VERSION 5.7 ;
BUSBITCHARS "[]" ;
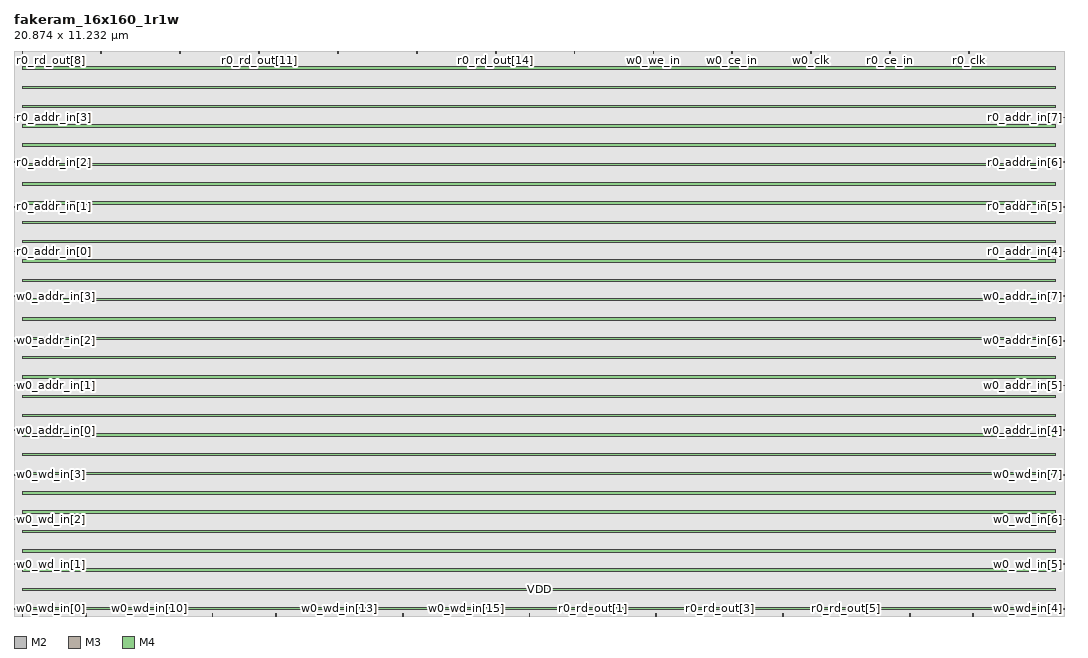
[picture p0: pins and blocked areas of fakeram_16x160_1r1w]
MACRO fakeram_16x160_1r1w
  FOREIGN fakeram_16x160_1r1w 0 0 ;
  SYMMETRY X Y R90 ;
  SIZE 20.874 BY 11.232 ;
  CLASS BLOCK ;
  PIN w0_wd_in[0]
    DIRECTION INPUT ;
    USE SIGNAL ;
    SHAPE ABUTMENT ;
    PORT
      LAYER M2 ;
      RECT 0.000 0.138 0.036 0.150 ;
    END
  END w0_wd_in[0]
  PIN w0_wd_in[1]
    DIRECTION INPUT ;
    USE SIGNAL ;
    SHAPE ABUTMENT ;
    PORT
      LAYER M2 ;
      RECT 0.000 1.026 0.036 1.038 ;
    END
  END w0_wd_in[1]
  PIN w0_wd_in[2]
    DIRECTION INPUT ;
    USE SIGNAL ;
    SHAPE ABUTMENT ;
    PORT
      LAYER M2 ;
      RECT 0.000 1.914 0.036 1.926 ;
    END
  END w0_wd_in[2]
  PIN w0_wd_in[3]
    DIRECTION INPUT ;
    USE SIGNAL ;
    SHAPE ABUTMENT ;
    PORT
      LAYER M2 ;
      RECT 0.000 2.802 0.036 2.814 ;
    END
  END w0_wd_in[3]
  PIN w0_wd_in[4]
    DIRECTION INPUT ;
    USE SIGNAL ;
    SHAPE ABUTMENT ;
    PORT
      LAYER M2 ;
      RECT 20.838 0.138 20.874 0.150 ;
    END
  END w0_wd_in[4]
  PIN w0_wd_in[5]
    DIRECTION INPUT ;
    USE SIGNAL ;
    SHAPE ABUTMENT ;
    PORT
      LAYER M2 ;
      RECT 20.838 1.026 20.874 1.038 ;
    END
  END w0_wd_in[5]
  PIN w0_wd_in[6]
    DIRECTION INPUT ;
    USE SIGNAL ;
    SHAPE ABUTMENT ;
    PORT
      LAYER M2 ;
      RECT 20.838 1.914 20.874 1.926 ;
    END
  END w0_wd_in[6]
  PIN w0_wd_in[7]
    DIRECTION INPUT ;
    USE SIGNAL ;
    SHAPE ABUTMENT ;
    PORT
      LAYER M2 ;
      RECT 20.838 2.802 20.874 2.814 ;
    END
  END w0_wd_in[7]
  PIN w0_wd_in[8]
    DIRECTION INPUT ;
    USE SIGNAL ;
    SHAPE ABUTMENT ;
    PORT
      LAYER M3 ;
      RECT 0.161 0.000 0.175 0.042 ;
    END
  END w0_wd_in[8]
  PIN w0_wd_in[9]
    DIRECTION INPUT ;
    USE SIGNAL ;
    SHAPE ABUTMENT ;
    PORT
      LAYER M3 ;
      RECT 1.421 0.000 1.435 0.042 ;
    END
  END w0_wd_in[9]
  PIN w0_wd_in[10]
    DIRECTION INPUT ;
    USE SIGNAL ;
    SHAPE ABUTMENT ;
    PORT
      LAYER M3 ;
      RECT 2.681 0.000 2.695 0.042 ;
    END
  END w0_wd_in[10]
  PIN w0_wd_in[11]
    DIRECTION INPUT ;
    USE SIGNAL ;
    SHAPE ABUTMENT ;
    PORT
      LAYER M3 ;
      RECT 3.941 0.000 3.955 0.042 ;
    END
  END w0_wd_in[11]
  PIN w0_wd_in[12]
    DIRECTION INPUT ;
    USE SIGNAL ;
    SHAPE ABUTMENT ;
    PORT
      LAYER M3 ;
      RECT 5.201 0.000 5.215 0.042 ;
    END
  END w0_wd_in[12]
  PIN w0_wd_in[13]
    DIRECTION INPUT ;
    USE SIGNAL ;
    SHAPE ABUTMENT ;
    PORT
      LAYER M3 ;
      RECT 6.461 0.000 6.475 0.042 ;
    END
  END w0_wd_in[13]
  PIN w0_wd_in[14]
    DIRECTION INPUT ;
    USE SIGNAL ;
    SHAPE ABUTMENT ;
    PORT
      LAYER M3 ;
      RECT 7.721 0.000 7.735 0.042 ;
    END
  END w0_wd_in[14]
  PIN w0_wd_in[15]
    DIRECTION INPUT ;
    USE SIGNAL ;
    SHAPE ABUTMENT ;
    PORT
      LAYER M3 ;
      RECT 8.981 0.000 8.995 0.042 ;
    END
  END w0_wd_in[15]
  PIN r0_rd_out[0]
    DIRECTION OUTPUT ;
    USE SIGNAL ;
    SHAPE ABUTMENT ;
    PORT
      LAYER M3 ;
      RECT 10.241 0.000 10.255 0.042 ;
    END
  END r0_rd_out[0]
  PIN r0_rd_out[1]
    DIRECTION OUTPUT ;
    USE SIGNAL ;
    SHAPE ABUTMENT ;
    PORT
      LAYER M3 ;
      RECT 11.501 0.000 11.515 0.042 ;
    END
  END r0_rd_out[1]
  PIN r0_rd_out[2]
    DIRECTION OUTPUT ;
    USE SIGNAL ;
    SHAPE ABUTMENT ;
    PORT
      LAYER M3 ;
      RECT 12.761 0.000 12.775 0.042 ;
    END
  END r0_rd_out[2]
  PIN r0_rd_out[3]
    DIRECTION OUTPUT ;
    USE SIGNAL ;
    SHAPE ABUTMENT ;
    PORT
      LAYER M3 ;
      RECT 14.021 0.000 14.035 0.042 ;
    END
  END r0_rd_out[3]
  PIN r0_rd_out[4]
    DIRECTION OUTPUT ;
    USE SIGNAL ;
    SHAPE ABUTMENT ;
    PORT
      LAYER M3 ;
      RECT 15.281 0.000 15.295 0.042 ;
    END
  END r0_rd_out[4]
  PIN r0_rd_out[5]
    DIRECTION OUTPUT ;
    USE SIGNAL ;
    SHAPE ABUTMENT ;
    PORT
      LAYER M3 ;
      RECT 16.541 0.000 16.555 0.042 ;
    END
  END r0_rd_out[5]
  PIN r0_rd_out[6]
    DIRECTION OUTPUT ;
    USE SIGNAL ;
    SHAPE ABUTMENT ;
    PORT
      LAYER M3 ;
      RECT 17.801 0.000 17.815 0.042 ;
    END
  END r0_rd_out[6]
  PIN r0_rd_out[7]
    DIRECTION OUTPUT ;
    USE SIGNAL ;
    SHAPE ABUTMENT ;
    PORT
      LAYER M3 ;
      RECT 19.061 0.000 19.075 0.042 ;
    END
  END r0_rd_out[7]
  PIN r0_rd_out[8]
    DIRECTION OUTPUT ;
    USE SIGNAL ;
    SHAPE ABUTMENT ;
    PORT
      LAYER M3 ;
      RECT 0.161 11.190 0.175 11.232 ;
    END
  END r0_rd_out[8]
  PIN r0_rd_out[9]
    DIRECTION OUTPUT ;
    USE SIGNAL ;
    SHAPE ABUTMENT ;
    PORT
      LAYER M3 ;
      RECT 1.729 11.190 1.743 11.232 ;
    END
  END r0_rd_out[9]
  PIN r0_rd_out[10]
    DIRECTION OUTPUT ;
    USE SIGNAL ;
    SHAPE ABUTMENT ;
    PORT
      LAYER M3 ;
      RECT 3.297 11.190 3.311 11.232 ;
    END
  END r0_rd_out[10]
  PIN r0_rd_out[11]
    DIRECTION OUTPUT ;
    USE SIGNAL ;
    SHAPE ABUTMENT ;
    PORT
      LAYER M3 ;
      RECT 4.865 11.190 4.879 11.232 ;
    END
  END r0_rd_out[11]
  PIN r0_rd_out[12]
    DIRECTION OUTPUT ;
    USE SIGNAL ;
    SHAPE ABUTMENT ;
    PORT
      LAYER M3 ;
      RECT 6.433 11.190 6.447 11.232 ;
    END
  END r0_rd_out[12]
  PIN r0_rd_out[13]
    DIRECTION OUTPUT ;
    USE SIGNAL ;
    SHAPE ABUTMENT ;
    PORT
      LAYER M3 ;
      RECT 8.001 11.190 8.015 11.232 ;
    END
  END r0_rd_out[13]
  PIN r0_rd_out[14]
    DIRECTION OUTPUT ;
    USE SIGNAL ;
    SHAPE ABUTMENT ;
    PORT
      LAYER M3 ;
      RECT 9.569 11.190 9.583 11.232 ;
    END
  END r0_rd_out[14]
  PIN r0_rd_out[15]
    DIRECTION OUTPUT ;
    USE SIGNAL ;
    SHAPE ABUTMENT ;
    PORT
      LAYER M3 ;
      RECT 11.137 11.190 11.151 11.232 ;
    END
  END r0_rd_out[15]
  PIN w0_addr_in[0]
    DIRECTION INPUT ;
    USE SIGNAL ;
    SHAPE ABUTMENT ;
    PORT
      LAYER M2 ;
      RECT 0.000 3.690 0.036 3.702 ;
    END
  END w0_addr_in[0]
  PIN w0_addr_in[1]
    DIRECTION INPUT ;
    USE SIGNAL ;
    SHAPE ABUTMENT ;
    PORT
      LAYER M2 ;
      RECT 0.000 4.578 0.036 4.590 ;
    END
  END w0_addr_in[1]
  PIN w0_addr_in[2]
    DIRECTION INPUT ;
    USE SIGNAL ;
    SHAPE ABUTMENT ;
    PORT
      LAYER M2 ;
      RECT 0.000 5.466 0.036 5.478 ;
    END
  END w0_addr_in[2]
  PIN w0_addr_in[3]
    DIRECTION INPUT ;
    USE SIGNAL ;
    SHAPE ABUTMENT ;
    PORT
      LAYER M2 ;
      RECT 0.000 6.354 0.036 6.366 ;
    END
  END w0_addr_in[3]
  PIN w0_addr_in[4]
    DIRECTION INPUT ;
    USE SIGNAL ;
    SHAPE ABUTMENT ;
    PORT
      LAYER M2 ;
      RECT 20.838 3.690 20.874 3.702 ;
    END
  END w0_addr_in[4]
  PIN w0_addr_in[5]
    DIRECTION INPUT ;
    USE SIGNAL ;
    SHAPE ABUTMENT ;
    PORT
      LAYER M2 ;
      RECT 20.838 4.578 20.874 4.590 ;
    END
  END w0_addr_in[5]
  PIN w0_addr_in[6]
    DIRECTION INPUT ;
    USE SIGNAL ;
    SHAPE ABUTMENT ;
    PORT
      LAYER M2 ;
      RECT 20.838 5.466 20.874 5.478 ;
    END
  END w0_addr_in[6]
  PIN w0_addr_in[7]
    DIRECTION INPUT ;
    USE SIGNAL ;
    SHAPE ABUTMENT ;
    PORT
      LAYER M2 ;
      RECT 20.838 6.354 20.874 6.366 ;
    END
  END w0_addr_in[7]
  PIN r0_addr_in[0]
    DIRECTION INPUT ;
    USE SIGNAL ;
    SHAPE ABUTMENT ;
    PORT
      LAYER M2 ;
      RECT 0.000 7.242 0.036 7.254 ;
    END
  END r0_addr_in[0]
  PIN r0_addr_in[1]
    DIRECTION INPUT ;
    USE SIGNAL ;
    SHAPE ABUTMENT ;
    PORT
      LAYER M2 ;
      RECT 0.000 8.130 0.036 8.142 ;
    END
  END r0_addr_in[1]
  PIN r0_addr_in[2]
    DIRECTION INPUT ;
    USE SIGNAL ;
    SHAPE ABUTMENT ;
    PORT
      LAYER M2 ;
      RECT 0.000 9.018 0.036 9.030 ;
    END
  END r0_addr_in[2]
  PIN r0_addr_in[3]
    DIRECTION INPUT ;
    USE SIGNAL ;
    SHAPE ABUTMENT ;
    PORT
      LAYER M2 ;
      RECT 0.000 9.906 0.036 9.918 ;
    END
  END r0_addr_in[3]
  PIN r0_addr_in[4]
    DIRECTION INPUT ;
    USE SIGNAL ;
    SHAPE ABUTMENT ;
    PORT
      LAYER M2 ;
      RECT 20.838 7.242 20.874 7.254 ;
    END
  END r0_addr_in[4]
  PIN r0_addr_in[5]
    DIRECTION INPUT ;
    USE SIGNAL ;
    SHAPE ABUTMENT ;
    PORT
      LAYER M2 ;
      RECT 20.838 8.130 20.874 8.142 ;
    END
  END r0_addr_in[5]
  PIN r0_addr_in[6]
    DIRECTION INPUT ;
    USE SIGNAL ;
    SHAPE ABUTMENT ;
    PORT
      LAYER M2 ;
      RECT 20.838 9.018 20.874 9.030 ;
    END
  END r0_addr_in[6]
  PIN r0_addr_in[7]
    DIRECTION INPUT ;
    USE SIGNAL ;
    SHAPE ABUTMENT ;
    PORT
      LAYER M2 ;
      RECT 20.838 9.906 20.874 9.918 ;
    END
  END r0_addr_in[7]
  PIN w0_we_in
    DIRECTION INPUT ;
    USE SIGNAL ;
    SHAPE ABUTMENT ;
    PORT
      LAYER M3 ;
      RECT 12.705 11.190 12.719 11.232 ;
    END
  END w0_we_in
  PIN w0_ce_in
    DIRECTION INPUT ;
    USE SIGNAL ;
    SHAPE ABUTMENT ;
    PORT
      LAYER M3 ;
      RECT 14.273 11.190 14.287 11.232 ;
    END
  END w0_ce_in
  PIN w0_clk
    DIRECTION INPUT ;
    USE SIGNAL ;
    SHAPE ABUTMENT ;
    PORT
      LAYER M3 ;
      RECT 15.841 11.190 15.855 11.232 ;
    END
  END w0_clk
  PIN r0_ce_in
    DIRECTION INPUT ;
    USE SIGNAL ;
    SHAPE ABUTMENT ;
    PORT
      LAYER M3 ;
      RECT 17.409 11.190 17.423 11.232 ;
    END
  END r0_ce_in
  PIN r0_clk
    DIRECTION INPUT ;
    USE SIGNAL ;
    SHAPE ABUTMENT ;
    PORT
      LAYER M3 ;
      RECT 18.977 11.190 18.991 11.232 ;
    END
  END r0_clk
  PIN VSS
    DIRECTION INOUT ;
    USE GROUND ;
    PORT
      LAYER M4 ;
      RECT 0.168 0.120 20.706 0.168 ;
      RECT 0.168 0.504 20.706 0.552 ;
      RECT 0.168 0.888 20.706 0.936 ;
      RECT 0.168 1.272 20.706 1.320 ;
      RECT 0.168 1.656 20.706 1.704 ;
      RECT 0.168 2.040 20.706 2.088 ;
      RECT 0.168 2.424 20.706 2.472 ;
      RECT 0.168 2.808 20.706 2.856 ;
      RECT 0.168 3.192 20.706 3.240 ;
      RECT 0.168 3.576 20.706 3.624 ;
      RECT 0.168 3.960 20.706 4.008 ;
      RECT 0.168 4.344 20.706 4.392 ;
      RECT 0.168 4.728 20.706 4.776 ;
      RECT 0.168 5.112 20.706 5.160 ;
      RECT 0.168 5.496 20.706 5.544 ;
      RECT 0.168 5.880 20.706 5.928 ;
      RECT 0.168 6.264 20.706 6.312 ;
      RECT 0.168 6.648 20.706 6.696 ;
      RECT 0.168 7.032 20.706 7.080 ;
      RECT 0.168 7.416 20.706 7.464 ;
      RECT 0.168 7.800 20.706 7.848 ;
      RECT 0.168 8.184 20.706 8.232 ;
      RECT 0.168 8.568 20.706 8.616 ;
      RECT 0.168 8.952 20.706 9.000 ;
      RECT 0.168 9.336 20.706 9.384 ;
      RECT 0.168 9.720 20.706 9.768 ;
      RECT 0.168 10.104 20.706 10.152 ;
      RECT 0.168 10.488 20.706 10.536 ;
      RECT 0.168 10.872 20.706 10.920 ;
    END
  END VSS
  PIN VDD
    DIRECTION INOUT ;
    USE POWER ;
    PORT
      LAYER M4 ;
      RECT 0.168 0.120 20.706 0.168 ;
      RECT 0.168 0.504 20.706 0.552 ;
      RECT 0.168 0.888 20.706 0.936 ;
      RECT 0.168 1.272 20.706 1.320 ;
      RECT 0.168 1.656 20.706 1.704 ;
      RECT 0.168 2.040 20.706 2.088 ;
      RECT 0.168 2.424 20.706 2.472 ;
      RECT 0.168 2.808 20.706 2.856 ;
      RECT 0.168 3.192 20.706 3.240 ;
      RECT 0.168 3.576 20.706 3.624 ;
      RECT 0.168 3.960 20.706 4.008 ;
      RECT 0.168 4.344 20.706 4.392 ;
      RECT 0.168 4.728 20.706 4.776 ;
      RECT 0.168 5.112 20.706 5.160 ;
      RECT 0.168 5.496 20.706 5.544 ;
      RECT 0.168 5.880 20.706 5.928 ;
      RECT 0.168 6.264 20.706 6.312 ;
      RECT 0.168 6.648 20.706 6.696 ;
      RECT 0.168 7.032 20.706 7.080 ;
      RECT 0.168 7.416 20.706 7.464 ;
      RECT 0.168 7.800 20.706 7.848 ;
      RECT 0.168 8.184 20.706 8.232 ;
      RECT 0.168 8.568 20.706 8.616 ;
      RECT 0.168 8.952 20.706 9.000 ;
      RECT 0.168 9.336 20.706 9.384 ;
      RECT 0.168 9.720 20.706 9.768 ;
      RECT 0.168 10.104 20.706 10.152 ;
      RECT 0.168 10.488 20.706 10.536 ;
      RECT 0.168 10.872 20.706 10.920 ;
    END
  END VDD
  OBS
    LAYER M1 ;
    RECT 0 0 20.874 11.232 ;
    LAYER M2 ;
    RECT 0 0 20.874 11.232 ;
    LAYER M3 ;
    RECT 0 0 20.874 11.232 ;
    LAYER M4 ;
    RECT 0 0 20.874 11.232 ;
  END
END fakeram_16x160_1r1w

END LIBRARY
